VERSION 5.8 ;
BUSBITCHARS "[]" ;
DIVIDERCHAR "/" ;

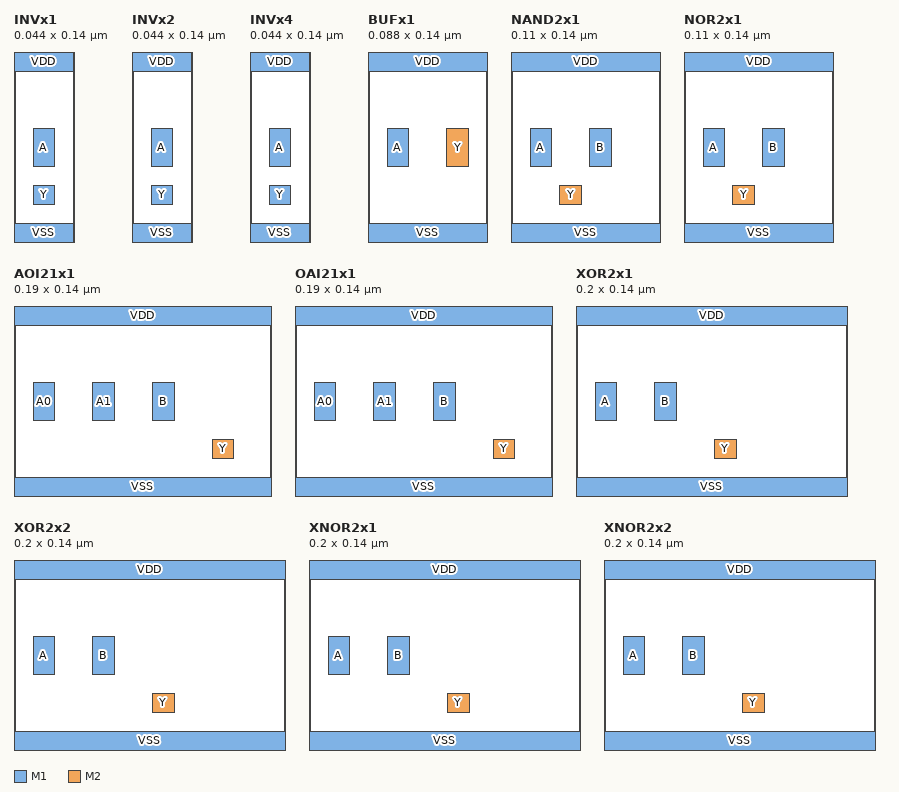
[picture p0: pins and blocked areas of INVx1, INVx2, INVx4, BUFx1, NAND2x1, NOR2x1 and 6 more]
MACRO INVx1
  CLASS CORE ;
  ORIGIN 0 0 ;
  SIZE 0.044 BY 0.140 ;
  SYMMETRY X Y ;
  SITE asap5_site ;
  PIN VDD
    DIRECTION INOUT ;
    USE POWER ;
    PORT
      LAYER M1 ;
        RECT 0.000 0.126 0.044 0.140 ;
    END
  END VDD
  PIN VSS
    DIRECTION INOUT ;
    USE GROUND ;
    PORT
      LAYER M1 ;
        RECT 0.000 0.000 0.044 0.014 ;
    END
  END VSS
  PIN A
    DIRECTION INPUT ;
    USE SIGNAL ;
    PORT
      LAYER M1 ;
        RECT 0.014 0.056 0.030 0.084 ;
    END
  END A
  PIN Y
    DIRECTION OUTPUT ;
    USE SIGNAL ;
    PORT
      LAYER M1 ;
        RECT 0.014 0.028 0.030 0.042 ;
    END
  END Y
END INVx1

MACRO INVx2
  CLASS CORE ;
  ORIGIN 0 0 ;
  SIZE 0.044 BY 0.140 ;
  SYMMETRY X Y ;
  SITE asap5_site ;
  PIN VDD
    DIRECTION INOUT ;
    USE POWER ;
    PORT
      LAYER M1 ;
        RECT 0.000 0.126 0.044 0.140 ;
    END
  END VDD
  PIN VSS
    DIRECTION INOUT ;
    USE GROUND ;
    PORT
      LAYER M1 ;
        RECT 0.000 0.000 0.044 0.014 ;
    END
  END VSS
  PIN A
    DIRECTION INPUT ;
    USE SIGNAL ;
    PORT
      LAYER M1 ;
        RECT 0.014 0.056 0.030 0.084 ;
    END
  END A
  PIN Y
    DIRECTION OUTPUT ;
    USE SIGNAL ;
    PORT
      LAYER M1 ;
        RECT 0.014 0.028 0.030 0.042 ;
    END
  END Y
END INVx2

MACRO INVx4
  CLASS CORE ;
  ORIGIN 0 0 ;
  SIZE 0.044 BY 0.140 ;
  SYMMETRY X Y ;
  SITE asap5_site ;
  PIN VDD
    DIRECTION INOUT ;
    USE POWER ;
    PORT
      LAYER M1 ;
        RECT 0.000 0.126 0.044 0.140 ;
    END
  END VDD
  PIN VSS
    DIRECTION INOUT ;
    USE GROUND ;
    PORT
      LAYER M1 ;
        RECT 0.000 0.000 0.044 0.014 ;
    END
  END VSS
  PIN A
    DIRECTION INPUT ;
    USE SIGNAL ;
    PORT
      LAYER M1 ;
        RECT 0.014 0.056 0.030 0.084 ;
    END
  END A
  PIN Y
    DIRECTION OUTPUT ;
    USE SIGNAL ;
    PORT
      LAYER M1 ;
        RECT 0.014 0.028 0.030 0.042 ;
    END
  END Y
END INVx4

MACRO BUFx1
  CLASS CORE ;
  ORIGIN 0 0 ;
  SIZE 0.088 BY 0.140 ;
  SYMMETRY X Y ;
  SITE asap5_site ;
  PIN VDD
    DIRECTION INOUT ;
    USE POWER ;
    PORT
      LAYER M1 ;
        RECT 0.000 0.126 0.088 0.140 ;
    END
  END VDD
  PIN VSS
    DIRECTION INOUT ;
    USE GROUND ;
    PORT
      LAYER M1 ;
        RECT 0.000 0.000 0.088 0.014 ;
    END
  END VSS
  PIN A
    DIRECTION INPUT ;
    USE SIGNAL ;
    PORT
      LAYER M1 ;
        RECT 0.014 0.056 0.030 0.084 ;
    END
  END A
  PIN Y
    DIRECTION OUTPUT ;
    USE SIGNAL ;
    PORT
      LAYER M2 ;
        RECT 0.058 0.056 0.074 0.084 ;
    END
  END Y
END BUFx1

MACRO NAND2x1
  CLASS CORE ;
  ORIGIN 0 0 ;
  SIZE 0.110 BY 0.140 ;
  SYMMETRY X Y ;
  SITE asap5_site ;
  PIN VDD
    DIRECTION INOUT ;
    USE POWER ;
    PORT
      LAYER M1 ;
        RECT 0.000 0.126 0.110 0.140 ;
    END
  END VDD
  PIN VSS
    DIRECTION INOUT ;
    USE GROUND ;
    PORT
      LAYER M1 ;
        RECT 0.000 0.000 0.110 0.014 ;
    END
  END VSS
  PIN A
    DIRECTION INPUT ;
    USE SIGNAL ;
    PORT
      LAYER M1 ;
        RECT 0.014 0.056 0.030 0.084 ;
    END
  END A
  PIN B
    DIRECTION INPUT ;
    USE SIGNAL ;
    PORT
      LAYER M1 ;
        RECT 0.058 0.056 0.074 0.084 ;
    END
  END B
  PIN Y
    DIRECTION OUTPUT ;
    USE SIGNAL ;
    PORT
      LAYER M2 ;
        RECT 0.036 0.028 0.052 0.042 ;
    END
  END Y
END NAND2x1

MACRO NOR2x1
  CLASS CORE ;
  ORIGIN 0 0 ;
  SIZE 0.110 BY 0.140 ;
  SYMMETRY X Y ;
  SITE asap5_site ;
  PIN VDD
    DIRECTION INOUT ;
    USE POWER ;
    PORT
      LAYER M1 ;
        RECT 0.000 0.126 0.110 0.140 ;
    END
  END VDD
  PIN VSS
    DIRECTION INOUT ;
    USE GROUND ;
    PORT
      LAYER M1 ;
        RECT 0.000 0.000 0.110 0.014 ;
    END
  END VSS
  PIN A
    DIRECTION INPUT ;
    USE SIGNAL ;
    PORT
      LAYER M1 ;
        RECT 0.014 0.056 0.030 0.084 ;
    END
  END A
  PIN B
    DIRECTION INPUT ;
    USE SIGNAL ;
    PORT
      LAYER M1 ;
        RECT 0.058 0.056 0.074 0.084 ;
    END
  END B
  PIN Y
    DIRECTION OUTPUT ;
    USE SIGNAL ;
    PORT
      LAYER M2 ;
        RECT 0.036 0.028 0.052 0.042 ;
    END
  END Y
END NOR2x1

MACRO AOI21x1
  CLASS CORE ;
  ORIGIN 0 0 ;
  SIZE 0.190 BY 0.140 ;
  SYMMETRY X Y ;
  SITE asap5_site ;
  PIN VDD
    DIRECTION INOUT ;
    USE POWER ;
    PORT
      LAYER M1 ;
        RECT 0.000 0.126 0.190 0.140 ;
    END
  END VDD
  PIN VSS
    DIRECTION INOUT ;
    USE GROUND ;
    PORT
      LAYER M1 ;
        RECT 0.000 0.000 0.190 0.014 ;
    END
  END VSS
  PIN A0
    DIRECTION INPUT ;
    USE SIGNAL ;
    PORT
      LAYER M1 ;
        RECT 0.014 0.056 0.030 0.084 ;
    END
  END A0
  PIN A1
    DIRECTION INPUT ;
    USE SIGNAL ;
    PORT
      LAYER M1 ;
        RECT 0.058 0.056 0.074 0.084 ;
    END
  END A1
  PIN B
    DIRECTION INPUT ;
    USE SIGNAL ;
    PORT
      LAYER M1 ;
        RECT 0.102 0.056 0.118 0.084 ;
    END
  END B
  PIN Y
    DIRECTION OUTPUT ;
    USE SIGNAL ;
    PORT
      LAYER M2 ;
        RECT 0.146 0.028 0.162 0.042 ;
    END
  END Y
END AOI21x1

MACRO OAI21x1
  CLASS CORE ;
  ORIGIN 0 0 ;
  SIZE 0.190 BY 0.140 ;
  SYMMETRY X Y ;
  SITE asap5_site ;
  PIN VDD
    DIRECTION INOUT ;
    USE POWER ;
    PORT
      LAYER M1 ;
        RECT 0.000 0.126 0.190 0.140 ;
    END
  END VDD
  PIN VSS
    DIRECTION INOUT ;
    USE GROUND ;
    PORT
      LAYER M1 ;
        RECT 0.000 0.000 0.190 0.014 ;
    END
  END VSS
  PIN A0
    DIRECTION INPUT ;
    USE SIGNAL ;
    PORT
      LAYER M1 ;
        RECT 0.014 0.056 0.030 0.084 ;
    END
  END A0
  PIN A1
    DIRECTION INPUT ;
    USE SIGNAL ;
    PORT
      LAYER M1 ;
        RECT 0.058 0.056 0.074 0.084 ;
    END
  END A1
  PIN B
    DIRECTION INPUT ;
    USE SIGNAL ;
    PORT
      LAYER M1 ;
        RECT 0.102 0.056 0.118 0.084 ;
    END
  END B
  PIN Y
    DIRECTION OUTPUT ;
    USE SIGNAL ;
    PORT
      LAYER M2 ;
        RECT 0.146 0.028 0.162 0.042 ;
    END
  END Y
END OAI21x1

MACRO XOR2x1
  CLASS CORE ;
  ORIGIN 0 0 ;
  SIZE 0.200 BY 0.140 ;
  SYMMETRY X Y ;
  SITE asap5_site ;
  PIN VDD
    DIRECTION INOUT ;
    USE POWER ;
    PORT
      LAYER M1 ;
        RECT 0.000 0.126 0.200 0.140 ;
    END
  END VDD
  PIN VSS
    DIRECTION INOUT ;
    USE GROUND ;
    PORT
      LAYER M1 ;
        RECT 0.000 0.000 0.200 0.014 ;
    END
  END VSS
  PIN A
    DIRECTION INPUT ;
    USE SIGNAL ;
    PORT
      LAYER M1 ;
        RECT 0.014 0.056 0.030 0.084 ;
    END
  END A
  PIN B
    DIRECTION INPUT ;
    USE SIGNAL ;
    PORT
      LAYER M1 ;
        RECT 0.058 0.056 0.074 0.084 ;
    END
  END B
  PIN Y
    DIRECTION OUTPUT ;
    USE SIGNAL ;
    PORT
      LAYER M1 ;
        RECT 0.102 0.028 0.118 0.042 ;
      LAYER M2 ;
        RECT 0.102 0.028 0.118 0.042 ;
    END
  END Y
END XOR2x1

MACRO XOR2x2
  CLASS CORE ;
  ORIGIN 0 0 ;
  SIZE 0.200 BY 0.140 ;
  SYMMETRY X Y ;
  SITE asap5_site ;
  PIN VDD
    DIRECTION INOUT ;
    USE POWER ;
    PORT
      LAYER M1 ;
        RECT 0.000 0.126 0.200 0.140 ;
    END
  END VDD
  PIN VSS
    DIRECTION INOUT ;
    USE GROUND ;
    PORT
      LAYER M1 ;
        RECT 0.000 0.000 0.200 0.014 ;
    END
  END VSS
  PIN A
    DIRECTION INPUT ;
    USE SIGNAL ;
    PORT
      LAYER M1 ;
        RECT 0.014 0.056 0.030 0.084 ;
    END
  END A
  PIN B
    DIRECTION INPUT ;
    USE SIGNAL ;
    PORT
      LAYER M1 ;
        RECT 0.058 0.056 0.074 0.084 ;
    END
  END B
  PIN Y
    DIRECTION OUTPUT ;
    USE SIGNAL ;
    PORT
      LAYER M1 ;
        RECT 0.102 0.028 0.118 0.042 ;
      LAYER M2 ;
        RECT 0.102 0.028 0.118 0.042 ;
    END
  END Y
END XOR2x2

MACRO XNOR2x1
  CLASS CORE ;
  ORIGIN 0 0 ;
  SIZE 0.200 BY 0.140 ;
  SYMMETRY X Y ;
  SITE asap5_site ;
  PIN VDD
    DIRECTION INOUT ;
    USE POWER ;
    PORT
      LAYER M1 ;
        RECT 0.000 0.126 0.200 0.140 ;
    END
  END VDD
  PIN VSS
    DIRECTION INOUT ;
    USE GROUND ;
    PORT
      LAYER M1 ;
        RECT 0.000 0.000 0.200 0.014 ;
    END
  END VSS
  PIN A
    DIRECTION INPUT ;
    USE SIGNAL ;
    PORT
      LAYER M1 ;
        RECT 0.014 0.056 0.030 0.084 ;
    END
  END A
  PIN B
    DIRECTION INPUT ;
    USE SIGNAL ;
    PORT
      LAYER M1 ;
        RECT 0.058 0.056 0.074 0.084 ;
    END
  END B
  PIN Y
    DIRECTION OUTPUT ;
    USE SIGNAL ;
    PORT
      LAYER M1 ;
        RECT 0.102 0.028 0.118 0.042 ;
      LAYER M2 ;
        RECT 0.102 0.028 0.118 0.042 ;
    END
  END Y
END XNOR2x1

MACRO XNOR2x2
  CLASS CORE ;
  ORIGIN 0 0 ;
  SIZE 0.200 BY 0.140 ;
  SYMMETRY X Y ;
  SITE asap5_site ;
  PIN VDD
    DIRECTION INOUT ;
    USE POWER ;
    PORT
      LAYER M1 ;
        RECT 0.000 0.126 0.200 0.140 ;
    END
  END VDD
  PIN VSS
    DIRECTION INOUT ;
    USE GROUND ;
    PORT
      LAYER M1 ;
        RECT 0.000 0.000 0.200 0.014 ;
    END
  END VSS
  PIN A
    DIRECTION INPUT ;
    USE SIGNAL ;
    PORT
      LAYER M1 ;
        RECT 0.014 0.056 0.030 0.084 ;
    END
  END A
  PIN B
    DIRECTION INPUT ;
    USE SIGNAL ;
    PORT
      LAYER M1 ;
        RECT 0.058 0.056 0.074 0.084 ;
    END
  END B
  PIN Y
    DIRECTION OUTPUT ;
    USE SIGNAL ;
    PORT
      LAYER M1 ;
        RECT 0.102 0.028 0.118 0.042 ;
      LAYER M2 ;
        RECT 0.102 0.028 0.118 0.042 ;
    END
  END Y
END XNOR2x2

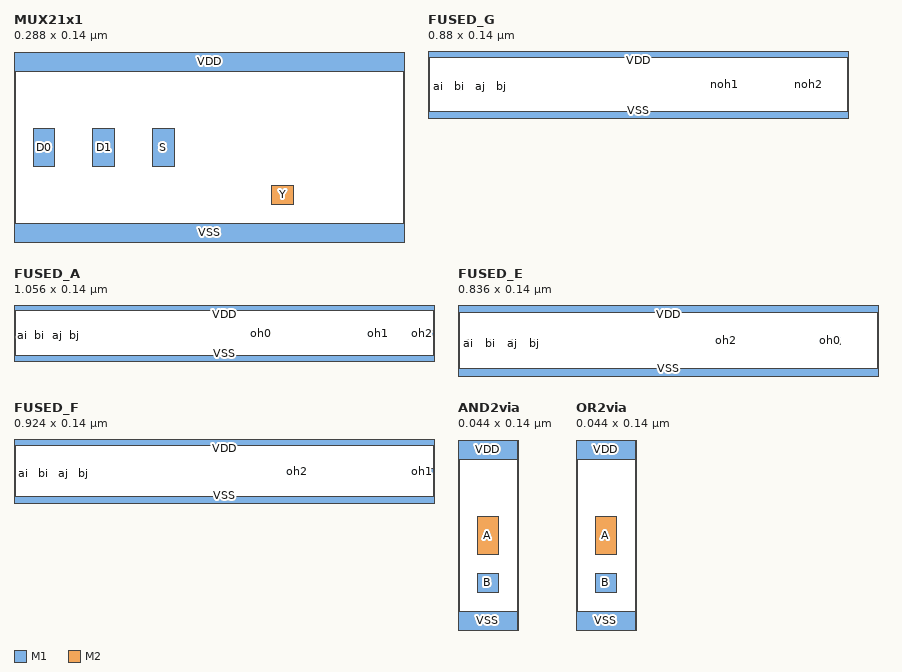
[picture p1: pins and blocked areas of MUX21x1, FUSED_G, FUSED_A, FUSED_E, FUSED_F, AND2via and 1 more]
MACRO MUX21x1
  CLASS CORE ;
  ORIGIN 0 0 ;
  SIZE 0.288 BY 0.140 ;
  SYMMETRY X Y ;
  SITE asap5_site ;
  PIN VDD
    DIRECTION INOUT ;
    USE POWER ;
    PORT
      LAYER M1 ;
        RECT 0.000 0.126 0.288 0.140 ;
    END
  END VDD
  PIN VSS
    DIRECTION INOUT ;
    USE GROUND ;
    PORT
      LAYER M1 ;
        RECT 0.000 0.000 0.288 0.014 ;
    END
  END VSS
  PIN D0
    DIRECTION INPUT ;
    USE SIGNAL ;
    PORT
      LAYER M1 ;
        RECT 0.014 0.056 0.030 0.084 ;
    END
  END D0
  PIN D1
    DIRECTION INPUT ;
    USE SIGNAL ;
    PORT
      LAYER M1 ;
        RECT 0.058 0.056 0.074 0.084 ;
    END
  END D1
  PIN S
    DIRECTION INPUT ;
    USE SIGNAL ;
    PORT
      LAYER M1 ;
        RECT 0.102 0.056 0.118 0.084 ;
    END
  END S
  PIN Y
    DIRECTION OUTPUT ;
    USE SIGNAL ;
    PORT
      LAYER M1 ;
        RECT 0.190 0.028 0.206 0.042 ;
      LAYER M2 ;
        RECT 0.190 0.028 0.206 0.042 ;
    END
  END Y
END MUX21x1

MACRO FUSED_G
  CLASS CORE ;
  ORIGIN 0 0 ;
  SIZE 0.880 BY 0.140 ;
  SYMMETRY X Y ;
  SITE asap5_site ;
  PIN VDD
    DIRECTION INOUT ;
    USE POWER ;
    PORT
      LAYER M1 ;
        RECT 0.000 0.126 0.880 0.140 ;
    END
  END VDD
  PIN VSS
    DIRECTION INOUT ;
    USE GROUND ;
    PORT
      LAYER M1 ;
        RECT 0.000 0.000 0.880 0.014 ;
    END
  END VSS
  PIN ai
    DIRECTION INPUT ;
    USE SIGNAL ;
    PORT
      LAYER M1 ;
        RECT 0.014 0.058 0.028 0.072 ;
    END
  END ai
  PIN bi
    DIRECTION INPUT ;
    USE SIGNAL ;
    PORT
      LAYER M1 ;
        RECT 0.058 0.058 0.072 0.072 ;
    END
  END bi
  PIN aj
    DIRECTION INPUT ;
    USE SIGNAL ;
    PORT
      LAYER M1 ;
        RECT 0.102 0.058 0.116 0.072 ;
    END
  END aj
  PIN bj
    DIRECTION INPUT ;
    USE SIGNAL ;
    PORT
      LAYER M1 ;
        RECT 0.146 0.058 0.160 0.072 ;
    END
  END bj
  PIN noh1
    DIRECTION OUTPUT ;
    USE SIGNAL ;
    PORT
      LAYER M1 ;
        RECT 0.615 0.063 0.629 0.077 ;
    END
  END noh1
  PIN noh2
    DIRECTION OUTPUT ;
    USE SIGNAL ;
    PORT
      LAYER M1 ;
        RECT 0.791 0.063 0.805 0.077 ;
    END
  END noh2
END FUSED_G

MACRO FUSED_A
  CLASS CORE ;
  ORIGIN 0 0 ;
  SIZE 1.056 BY 0.140 ;
  SYMMETRY X Y ;
  SITE asap5_site ;
  PIN VDD
    DIRECTION INOUT ;
    USE POWER ;
    PORT
      LAYER M1 ;
        RECT 0.000 0.126 1.056 0.140 ;
    END
  END VDD
  PIN VSS
    DIRECTION INOUT ;
    USE GROUND ;
    PORT
      LAYER M1 ;
        RECT 0.000 0.000 1.056 0.014 ;
    END
  END VSS
  PIN ai
    DIRECTION INPUT ;
    USE SIGNAL ;
    PORT
      LAYER M1 ;
        RECT 0.014 0.058 0.028 0.072 ;
    END
  END ai
  PIN bi
    DIRECTION INPUT ;
    USE SIGNAL ;
    PORT
      LAYER M1 ;
        RECT 0.058 0.058 0.072 0.072 ;
    END
  END bi
  PIN aj
    DIRECTION INPUT ;
    USE SIGNAL ;
    PORT
      LAYER M1 ;
        RECT 0.102 0.058 0.116 0.072 ;
    END
  END aj
  PIN bj
    DIRECTION INPUT ;
    USE SIGNAL ;
    PORT
      LAYER M1 ;
        RECT 0.146 0.058 0.160 0.072 ;
    END
  END bj
  PIN oh0
    DIRECTION OUTPUT ;
    USE SIGNAL ;
    PORT
      LAYER M1 ;
        RECT 0.615 0.063 0.629 0.077 ;
    END
  END oh0
  PIN oh1
    DIRECTION OUTPUT ;
    USE SIGNAL ;
    PORT
      LAYER M1 ;
        RECT 0.909 0.063 0.923 0.077 ;
    END
  END oh1
  PIN oh2
    DIRECTION OUTPUT ;
    USE SIGNAL ;
    PORT
      LAYER M1 ;
        RECT 1.041 0.063 1.055 0.077 ;
    END
  END oh2
END FUSED_A

MACRO FUSED_E
  CLASS CORE ;
  ORIGIN 0 0 ;
  SIZE 0.836 BY 0.140 ;
  SYMMETRY X Y ;
  SITE asap5_site ;
  PIN VDD
    DIRECTION INOUT ;
    USE POWER ;
    PORT
      LAYER M1 ;
        RECT 0.000 0.126 0.836 0.140 ;
    END
  END VDD
  PIN VSS
    DIRECTION INOUT ;
    USE GROUND ;
    PORT
      LAYER M1 ;
        RECT 0.000 0.000 0.836 0.014 ;
    END
  END VSS
  PIN ai
    DIRECTION INPUT ;
    USE SIGNAL ;
    PORT
      LAYER M1 ;
        RECT 0.014 0.058 0.028 0.072 ;
    END
  END ai
  PIN bi
    DIRECTION INPUT ;
    USE SIGNAL ;
    PORT
      LAYER M1 ;
        RECT 0.058 0.058 0.072 0.072 ;
    END
  END bi
  PIN aj
    DIRECTION INPUT ;
    USE SIGNAL ;
    PORT
      LAYER M1 ;
        RECT 0.102 0.058 0.116 0.072 ;
    END
  END aj
  PIN bj
    DIRECTION INPUT ;
    USE SIGNAL ;
    PORT
      LAYER M1 ;
        RECT 0.146 0.058 0.160 0.072 ;
    END
  END bj
  PIN oh0
    DIRECTION OUTPUT ;
    USE SIGNAL ;
    PORT
      LAYER M1 ;
        RECT 0.733 0.063 0.747 0.077 ;
    END
  END oh0
  PIN oh1
    DIRECTION OUTPUT ;
    USE SIGNAL ;
    PORT
      LAYER M1 ;
        RECT 0.747 0.063 0.761 0.077 ;
    END
  END oh1
  PIN oh2
    DIRECTION OUTPUT ;
    USE SIGNAL ;
    PORT
      LAYER M1 ;
        RECT 0.527 0.063 0.541 0.077 ;
    END
  END oh2
END FUSED_E

MACRO FUSED_F
  CLASS CORE ;
  ORIGIN 0 0 ;
  SIZE 0.924 BY 0.140 ;
  SYMMETRY X Y ;
  SITE asap5_site ;
  PIN VDD
    DIRECTION INOUT ;
    USE POWER ;
    PORT
      LAYER M1 ;
        RECT 0.000 0.126 0.924 0.140 ;
    END
  END VDD
  PIN VSS
    DIRECTION INOUT ;
    USE GROUND ;
    PORT
      LAYER M1 ;
        RECT 0.000 0.000 0.924 0.014 ;
    END
  END VSS
  PIN ai
    DIRECTION INPUT ;
    USE SIGNAL ;
    PORT
      LAYER M1 ;
        RECT 0.014 0.058 0.028 0.072 ;
    END
  END ai
  PIN bi
    DIRECTION INPUT ;
    USE SIGNAL ;
    PORT
      LAYER M1 ;
        RECT 0.058 0.058 0.072 0.072 ;
    END
  END bi
  PIN aj
    DIRECTION INPUT ;
    USE SIGNAL ;
    PORT
      LAYER M1 ;
        RECT 0.102 0.058 0.116 0.072 ;
    END
  END aj
  PIN bj
    DIRECTION INPUT ;
    USE SIGNAL ;
    PORT
      LAYER M1 ;
        RECT 0.146 0.058 0.160 0.072 ;
    END
  END bj
  PIN oh1
    DIRECTION OUTPUT ;
    USE SIGNAL ;
    PORT
      LAYER M1 ;
        RECT 0.909 0.063 0.923 0.077 ;
    END
  END oh1
  PIN oh2
    DIRECTION OUTPUT ;
    USE SIGNAL ;
    PORT
      LAYER M1 ;
        RECT 0.615 0.063 0.629 0.077 ;
    END
  END oh2
END FUSED_F

MACRO AND2via
  CLASS CORE ;
  ORIGIN 0 0 ;
  SIZE 0.044 BY 0.140 ;
  SYMMETRY X Y ;
  SITE asap5_site ;
  PIN VDD
    DIRECTION INOUT ;
    USE POWER ;
    PORT
      LAYER M1 ;
        RECT 0.000 0.126 0.044 0.140 ;
    END
  END VDD
  PIN VSS
    DIRECTION INOUT ;
    USE GROUND ;
    PORT
      LAYER M1 ;
        RECT 0.000 0.000 0.044 0.014 ;
    END
  END VSS
  PIN A
    DIRECTION INPUT ;
    USE SIGNAL ;
    PORT
      LAYER M1 ;
        RECT 0.014 0.056 0.030 0.084 ;
    END
  END A
  PIN B
    DIRECTION INPUT ;
    USE SIGNAL ;
    PORT
      LAYER M1 ;
        RECT 0.014 0.028 0.030 0.042 ;
    END
  END B
  PIN Y
    DIRECTION OUTPUT ;
    USE SIGNAL ;
    PORT
      LAYER M2 ;
        RECT 0.014 0.056 0.030 0.084 ;
    END
  END Y
END AND2via

MACRO OR2via
  CLASS CORE ;
  ORIGIN 0 0 ;
  SIZE 0.044 BY 0.140 ;
  SYMMETRY X Y ;
  SITE asap5_site ;
  PIN VDD
    DIRECTION INOUT ;
    USE POWER ;
    PORT
      LAYER M1 ;
        RECT 0.000 0.126 0.044 0.140 ;
    END
  END VDD
  PIN VSS
    DIRECTION INOUT ;
    USE GROUND ;
    PORT
      LAYER M1 ;
        RECT 0.000 0.000 0.044 0.014 ;
    END
  END VSS
  PIN A
    DIRECTION INPUT ;
    USE SIGNAL ;
    PORT
      LAYER M1 ;
        RECT 0.014 0.056 0.030 0.084 ;
    END
  END A
  PIN B
    DIRECTION INPUT ;
    USE SIGNAL ;
    PORT
      LAYER M1 ;
        RECT 0.014 0.028 0.030 0.042 ;
    END
  END B
  PIN Y
    DIRECTION OUTPUT ;
    USE SIGNAL ;
    PORT
      LAYER M2 ;
        RECT 0.014 0.056 0.030 0.084 ;
    END
  END Y
END OR2via

END LIBRARY
